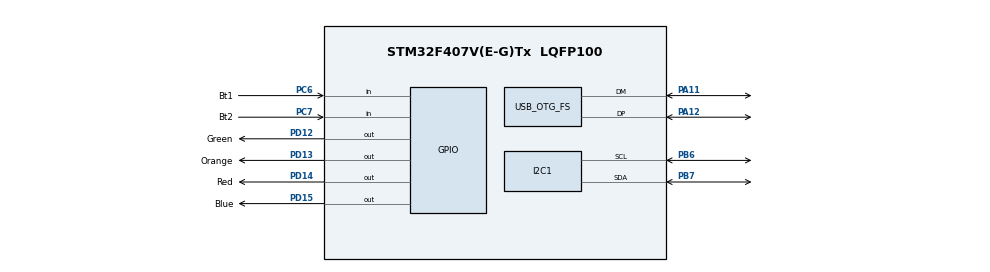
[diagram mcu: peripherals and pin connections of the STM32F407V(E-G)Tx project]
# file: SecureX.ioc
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I2C1.I2C_Mode=I2C_Fast
Mcu.Family=STM32F4
Mcu.Name=STM32F407V(E-G)Tx
Mcu.Package=LQFP100
NVIC.HASH_RNG_IRQn=true\:0\:0\:false\:false\:true\:true\:true\:true
NVIC.OTG_FS_IRQn=true\:0\:0\:false\:false\:true\:true\:true\:true
NVIC.PriorityGroup=NVIC_PRIORITYGROUP_0
NVIC.TIM2_IRQn=true\:0\:0\:false\:false\:true\:true\:true\:true
PA11.Mode=Device_Only
PA11.Signal=USB_OTG_FS_DM
PA12.Mode=Device_Only
PA12.Signal=USB_OTG_FS_DP
PA13.Mode=Trace_Asynchronous_SW
PA13.Signal=SYS_JTMS-SWDIO
PA14.Mode=Trace_Asynchronous_SW
PA14.Signal=SYS_JTCK-SWCLK
PB3.Mode=Trace_Asynchronous_SW
PB3.Signal=SYS_JTDO-SWO
PB6.Mode=I2C
PB6.Signal=I2C1_SCL
PB7.Mode=I2C
PB7.Signal=I2C1_SDA
PC6.GPIO_Label=Bt1
PC6.Signal=GPIO_Input
PC7.GPIO_Label=Bt2
PC7.Signal=GPIO_Input
PD12.GPIO_Label=Green
PD12.Signal=GPIO_Output
PD13.GPIO_Label=Orange
PD13.Signal=GPIO_Output
PD14.GPIO_Label=Red
PD14.Signal=GPIO_Output
PD15.GPIO_Label=Blue
PD15.Signal=GPIO_Output
PH0-OSC_IN.Mode=HSE-External-Oscillator
PH0-OSC_IN.Signal=RCC_OSC_IN
PH1-OSC_OUT.Mode=HSE-External-Oscillator
PH1-OSC_OUT.Signal=RCC_OSC_OUT
ProjectManager.HeapSize=0x200
ProjectManager.StackSize=0x400
ProjectManager.TargetToolchain=STM32CubeIDE
RCC.48MHZClocksFreq_Value=48000000
RCC.AHBFreq_Value=168000000
RCC.APB1CLKDivider=RCC_HCLK_DIV8
RCC.APB1Freq_Value=21000000
RCC.APB1TimFreq_Value=42000000
RCC.APB2CLKDivider=RCC_HCLK_DIV2
RCC.APB2Freq_Value=84000000
RCC.APB2TimFreq_Value=168000000
RCC.CortexFreq_Value=168000000
RCC.HCLKFreq_Value=168000000
RCC.HSE_VALUE=8000000
RCC.HSI_VALUE=16000000
RCC.LSE_VALUE=32768
RCC.PLLM=8
RCC.PLLN=336
RCC.PLLQ=7
RCC.SYSCLKFreq_VALUE=168000000
RCC.SYSCLKSource=RCC_SYSCLKSOURCE_PLLCLK
RCC.VCOOutputFreq_Value=336000000
TIM2.Period=1000
TIM2.Prescaler=42000
TIM2.TIM_MasterOutputTrigger=TIM_TRGO_UPDATE
USB_DEVICE.CLASS_NAME_FS=CDC
USB_DEVICE.VirtualMode-CDC_FS=Cdc
USB_DEVICE.VirtualModeFS=Cdc_FS
USB_OTG_FS.VirtualMode=Device_Only
VP_CRC_VS_CRC.Mode=CRC_Activate
VP_RNG_VS_RNG.Mode=RNG_Activate
VP_TIM2_VS_ClockSourceINT.Mode=Internal
VP_USB_DEVICE_VS_USB_DEVICE_CDC_FS.Mode=CDC_FS
board=STM32F407G-DISC1

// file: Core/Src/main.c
/* USER CODE BEGIN Header */
/**
 ******************************************************************************
 * @file           : main.c
 * @brief          : Main program body
 ******************************************************************************
 * @attention
 *
 * Copyright (c) 2024 STMicroelectronics.
 * All rights reserved.
 *
 * This software is licensed under terms that can be found in the LICENSE file
 * in the root directory of this software component.
 * If no LICENSE file comes with this software, it is provided AS-IS.
 *
 ******************************************************************************
 */
/* USER CODE END Header */
#include "main.h"
#include "usb_device.h"
/* USER CODE BEGIN Includes */
#include "usbd_cdc_if.h"
/* USER CODE END Includes */

/* USER CODE BEGIN PD */

cmox_sha256_handle_t sha256_ctx;

/* USER CODE END PD */

CRC_HandleTypeDef hcrc;

I2C_HandleTypeDef hi2c1;

RNG_HandleTypeDef hrng;

TIM_HandleTypeDef htim2;

/* USER CODE BEGIN PV */
uint8_t Brand_new = 0;
uint8_t GlobalSalt[8];
uint8_t LocalSalt[8];
uint8_t IV[16];
uint8_t password[12];
uint8_t MasterKey[16];    //128 bit
uint8_t user_num=0;
uint8_t CurrentUser;
uint8_t CurrentPassword[12];
uint8_t CurrentMasterKey[16];
uint8_t CurrentLocalSalt[8];
uint8_t CurrentIV[16];
uint8_t WrongPassword=0;
StateType state=Lock;
StateType MenuState=Lock;
bool TimerState=false;    //false is lock true unlock
bool DeviceState=false;   //false is lock true unlock
uint32_t Timer =0;
/* USER CODE END PV */

void SystemClock_Config(void);
static void MX_GPIO_Init(void);
static void MX_I2C1_Init(void);
static void MX_RNG_Init(void);
static void MX_TIM2_Init(void);
static void MX_CRC_Init(void);

/* USER CODE BEGIN 0 */
void I2C_Scan() {
  printf("Scanning I2C bus...\n");

  for (uint8_t i = 1; i < 128; i++) {  // I2C addresses range from 1 to 127
    if (HAL_I2C_IsDeviceReady(&hi2c1, (i << 1), 1, HAL_MAX_DELAY) == HAL_OK) {
      DEBUG_PRINT("Device found at 0x%02X\n", i);
    }
  }

  printf("Scan complete.\n");
}

void CDC_recieveCALLBACK(uint8_t *buf, uint32_t len) {
  uint8_t hwinfo[33] = {
      0x00, 0x02, 0x00, 0x00, 0x00, 0x00, 0x00, 0x00, 0x00,
      0x00, 0x00, 0x00, 0x00, 0x00, 0x00, 0x00, 0x00,
      0x00, 0x00, 0x00, 0x00, 0x00, 0x00, 0x00, 0x00,
      0x00, 0x00, 0x00, 0x00, 0x00, 0x00, 0x00, 0x01,
  };
  DEBUG_PRINT("Checking usb\n");
  printArray("Input data", buf, sizeof(buf));
  if (buf[0] == 0) {
    // Command 0: Check device status
    MY_FLASH_ReadN(BrandNew_address, &Brand_new, 1, DATA_TYPE_8);
    if (Brand_new == 0) {
      hwinfo[0] = 2; // Brand new device status
      CDC_Transmit_FS(hwinfo, 33); // Transmit status information
    } else if (DeviceState) {
      hwinfo[0] = 1; // Device unlocked status
      CDC_Transmit_FS(hwinfo, 33); // Transmit status information
    } else {
      hwinfo[0] = 0; // Device locked status
      CDC_Transmit_FS(hwinfo, 33); // Transmit status information
    }
  } else if (buf[0] == 1) {
    // Command 1: Toggle device state (Lock)
    if (DeviceState) {
      hwinfo[0] = 0; // Lock device
      CDC_Transmit_FS(hwinfo, 33); // Transmit status information
      DeviceState = 0; // Set device state to locked
      TimerState = 1; // Start timer
    } else {
      hwinfo[0] = 1; // device is a lock
      CDC_Transmit_FS(hwinfo, 33); // Transmit status information
    }
  } else if (buf[0] == 2) {
    // Command 2: Perform cryptographic operation
    if (DeviceState) {
      // Read the key from the received buffer
      uint8_t Key[9] = { buf[1], buf[2], buf[3], buf[4], buf[5], buf[6], buf[7], buf[8], buf[9] };
      printArray("Input ID", Key, sizeof(Key));
      printArray("Current master key", CurrentMasterKey, sizeof(CurrentMasterKey));
      // Initialize variables for key generation operation
      uint32_t carry = 0;
      uint8_t result[16];

      // Perform the key generation calculation
      for (int i = 0; i < 16; i++) {
        uint32_t sum = CurrentMasterKey[i] + (i < 9 ? Key[i] : 0) + carry;
        result[i] = sum & 0xFF;
        carry = (sum >> 8) & 0xFF;
      }
      printArray("Addition result of Masterkey + ID ", result, sizeof(result));
      // Calculate SHA-256 hash of the result
      uint8_t computed_hash[32];
      sha256(result, computed_hash, sizeof(result));
      printArray("Generated key ", computed_hash, sizeof(computed_hash));
      // Transmit the computed hash
      CDC_Transmit_FS(computed_hash, 32);
    }
  }
}
/* USER CODE END 0 */

int main(void)
{

  /* MCU Configuration--------------------------------------------------------*/

  /* Reset of all peripherals, Initializes the Flash interface and the Systick. */
  HAL_Init();

  /* Configure the system clock */
  SystemClock_Config();

  /* Initialize all configured peripherals */
  MX_GPIO_Init();
  MX_I2C1_Init();
  MX_RNG_Init();
  MX_TIM2_Init();
  MX_USB_DEVICE_Init();
  MX_CRC_Init();
  /* USER CODE BEGIN 2 */
  DEBUG_PRINT("Power up...!\n");
  MY_FLASH_SetSectorAddrs(sector_name, sector_base_address);
  ssd1306_Init();
  HAL_TIM_Base_Start_IT(&htim2);
  //write_flash(BrandNew_address, &Brand_new, 1);
  //write_flash(Nusers_address, &user_num, 1);
  //write_flash(WrongPassword_address, &WrongPassword, 1);
  I2C_Scan();
  Startup();
  /* USER CODE END 2 */

  /* Infinite loop */
  /* USER CODE BEGIN WHILE */
  while (1)
  {
    if(state == Lock)LockDevice();
    if(state == Reset)ResetFactory();
    if(state == Timeout)TimeoutMenu();
    if(state == Enrollment)Enroll();
    if(state == Menu)MainMenu();
    /* USER CODE END WHILE */
  }
}

void SystemClock_Config(void)
{
  RCC_OscInitTypeDef RCC_OscInitStruct = {0};
  RCC_ClkInitTypeDef RCC_ClkInitStruct = {0};

  /** Configure the main internal regulator output voltage
   */
  __HAL_RCC_PWR_CLK_ENABLE();
  __HAL_PWR_VOLTAGESCALING_CONFIG(PWR_REGULATOR_VOLTAGE_SCALE1);

  /** Initializes the RCC Oscillators according to the specified parameters
   * in the RCC_OscInitTypeDef structure.
   */
  RCC_OscInitStruct.OscillatorType = RCC_OSCILLATORTYPE_HSE;
  RCC_OscInitStruct.HSEState = RCC_HSE_ON;
  RCC_OscInitStruct.PLL.PLLState = RCC_PLL_ON;
  RCC_OscInitStruct.PLL.PLLSource = RCC_PLLSOURCE_HSE;
  RCC_OscInitStruct.PLL.PLLM = 4;
  RCC_OscInitStruct.PLL.PLLN = 72;
  RCC_OscInitStruct.PLL.PLLP = RCC_PLLP_DIV2;
  RCC_OscInitStruct.PLL.PLLQ = 3;
  if (HAL_RCC_OscConfig(&RCC_OscInitStruct) != HAL_OK)
  {
    Error_Handler();
  }

  /** Initializes the CPU, AHB and APB buses clocks
   */
  RCC_ClkInitStruct.ClockType = RCC_CLOCKTYPE_HCLK|RCC_CLOCKTYPE_SYSCLK
      |RCC_CLOCKTYPE_PCLK1|RCC_CLOCKTYPE_PCLK2;
  RCC_ClkInitStruct.SYSCLKSource = RCC_SYSCLKSOURCE_PLLCLK;
  RCC_ClkInitStruct.AHBCLKDivider = RCC_SYSCLK_DIV1;
  RCC_ClkInitStruct.APB1CLKDivider = RCC_HCLK_DIV2;
  RCC_ClkInitStruct.APB2CLKDivider = RCC_HCLK_DIV1;

  if (HAL_RCC_ClockConfig(&RCC_ClkInitStruct, FLASH_LATENCY_2) != HAL_OK)
  {
    Error_Handler();
  }
}

static void MX_CRC_Init(void)
{

  hcrc.Instance = CRC;
  if (HAL_CRC_Init(&hcrc) != HAL_OK)
  {
    Error_Handler();
  }

}

static void MX_I2C1_Init(void)
{

  hi2c1.Instance = I2C1;
  hi2c1.Init.ClockSpeed = 400000;
  hi2c1.Init.DutyCycle = I2C_DUTYCYCLE_2;
  hi2c1.Init.OwnAddress1 = 0;
  hi2c1.Init.AddressingMode = I2C_ADDRESSINGMODE_7BIT;
  hi2c1.Init.DualAddressMode = I2C_DUALADDRESS_DISABLE;
  hi2c1.Init.OwnAddress2 = 0;
  hi2c1.Init.GeneralCallMode = I2C_GENERALCALL_DISABLE;
  hi2c1.Init.NoStretchMode = I2C_NOSTRETCH_DISABLE;
  if (HAL_I2C_Init(&hi2c1) != HAL_OK)
  {
    Error_Handler();
  }

}

static void MX_RNG_Init(void)
{

  hrng.Instance = RNG;
  if (HAL_RNG_Init(&hrng) != HAL_OK)
  {
    Error_Handler();
  }

}

static void MX_TIM2_Init(void)
{

  TIM_ClockConfigTypeDef sClockSourceConfig = {0};
  TIM_MasterConfigTypeDef sMasterConfig = {0};

  htim2.Instance = TIM2;
  htim2.Init.Prescaler = 42000;
  htim2.Init.CounterMode = TIM_COUNTERMODE_UP;
  htim2.Init.Period = 1000;
  htim2.Init.ClockDivision = TIM_CLOCKDIVISION_DIV1;
  htim2.Init.AutoReloadPreload = TIM_AUTORELOAD_PRELOAD_DISABLE;
  if (HAL_TIM_Base_Init(&htim2) != HAL_OK)
  {
    Error_Handler();
  }
  sClockSourceConfig.ClockSource = TIM_CLOCKSOURCE_INTERNAL;
  if (HAL_TIM_ConfigClockSource(&htim2, &sClockSourceConfig) != HAL_OK)
  {
    Error_Handler();
  }
  sMasterConfig.MasterOutputTrigger = TIM_TRGO_RESET;
  sMasterConfig.MasterSlaveMode = TIM_MASTERSLAVEMODE_DISABLE;
  if (HAL_TIMEx_MasterConfigSynchronization(&htim2, &sMasterConfig) != HAL_OK)
  {
    Error_Handler();
  }

}

static void MX_GPIO_Init(void)
{
  GPIO_InitTypeDef GPIO_InitStruct = {0};

  /* GPIO Ports Clock Enable */
  __HAL_RCC_GPIOH_CLK_ENABLE();
  __HAL_RCC_GPIOC_CLK_ENABLE();
  __HAL_RCC_GPIOA_CLK_ENABLE();
  __HAL_RCC_GPIOB_CLK_ENABLE();

  /*Configure GPIO pins : UP_Pin DOWN_Pin */
  GPIO_InitStruct.Pin = UP_Pin|DOWN_Pin;
  GPIO_InitStruct.Mode = GPIO_MODE_INPUT;
  GPIO_InitStruct.Pull = GPIO_NOPULL;
  HAL_GPIO_Init(GPIOC, &GPIO_InitStruct);

}

void Error_Handler(void)
{
  __disable_irq();
  while (1)
  {
  }
}
